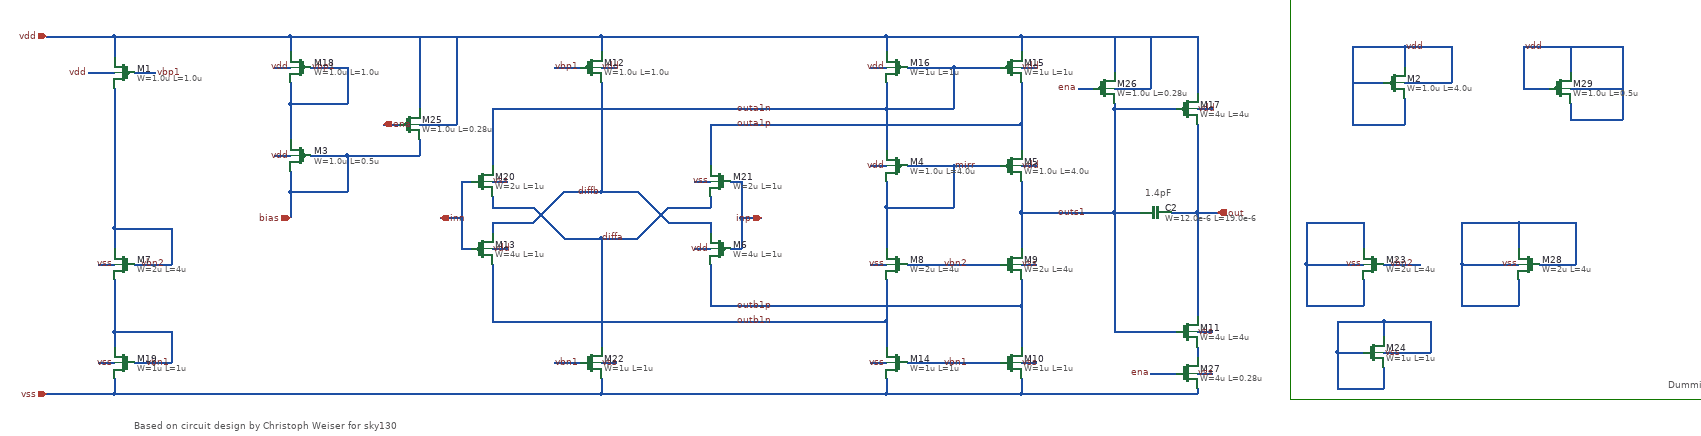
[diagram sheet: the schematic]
v {xschem version=3.4.6 file_version=1.2}
G {}
K {}
V {}
S {}
E {}
P 4 5 1810 -650 1810 140 2660 140 2660 -650 1810 -650 {}
T {Dummies} 2540 100 0 0 0.4 0.4 {}
T {Based on circuit design by Christoph Weiser for sky130} -420 180 0 0 0.4 0.4 {}
T {1.4pF} 1530 -270 0 0 0.3 0.3 {}
N 1000 -500 1030 -500 { lab=vdd}
N 1290 -500 1320 -500 { lab=vdd}
N 660 -280 690 -280 { lab=vss}
N 270 -280 300 -280 { lab=vss}
N 1030 -560 1030 -530 { lab=vdd}
N 270 -250 270 -230 { lab=diffa}
N 480 70 510 70 { lab=vss}
N -490 70 -460 70 { lab=vss}
N -420 -120 -350 -120 { lab=vbn2}
N -490 -120 -460 -120 { lab=vss}
N -420 70 -350 70 { lab=vbn1}
N -460 130 480 130 { lab=vss}
N -150 -500 -120 -500 { lab=vdd}
N 1290 -310 1320 -310 { lab=vdd}
N 1000 -310 1030 -310 { lab=vdd}
N 1160 -310 1250 -310 { lab=mirr}
N 1000 -120 1030 -120 { lab=vss}
N 1290 -120 1320 -120 { lab=vss}
N 1290 -220 1470 -220 { lab=outs1}
N 1000 70 1030 70 { lab=vss}
N 1290 70 1320 70 { lab=vss}
N -590 130 -460 130 { lab=vss}
N 1160 -500 1250 -500 { lab=outa1n}
N 1290 -560 1290 -530 { lab=vdd}
N 1030 -560 1290 -560 { lab=vdd}
N -80 -500 -10 -500 { lab=vbp1}
N 480 -560 1030 -560 { lab=vdd}
N -460 -190 -460 -150 { lab=vbn2}
N -460 10 -350 10 { lab=vbn1}
N -350 10 -350 70 { lab=vbn1}
N -350 -190 -350 -120 { lab=vbn2}
N -460 -190 -350 -190 { lab=vbn2}
N 390 70 450 70 { lab=vbn1}
N -150 -330 -120 -330 { lab=vdd}
N -80 -330 -10 -330 { lab=bias}
N 270 -420 270 -310 { lab=outa1n}
N 690 -390 690 -310 { lab=outa1p}
N -10 -330 -10 -260 { lab=bias}
N -460 10 -460 40 { lab=vbn1}
N -10 -500 -10 -430 { lab=vbp1}
N -120 -560 -120 -530 { lab=vdd}
N -120 -260 -10 -260 { lab=bias}
N -120 -430 -120 -360 { lab=vbp1}
N -120 -430 -10 -430 { lab=vbp1}
N 170 -210 210 -210 { lab=inn}
N 210 -150 230 -150 { lab=inn}
N -460 100 -460 130 { lab=vss}
N 270 -150 300 -150 { lab=vdd}
N 660 -150 690 -150 { lab=vdd}
N 270 -200 270 -180 { lab=diffb}
N 270 -200 350 -200 { lab=diffb}
N 350 -200 410 -260 { lab=diffb}
N 270 -230 350 -230 { lab=diffa}
N 350 -230 410 -170 { lab=diffa}
N 690 -250 690 -230 { lab=diffa}
N 690 -200 690 -180 { lab=diffb}
N 610 -200 690 -200 { lab=diffb}
N 550 -260 610 -200 { lab=diffb}
N 610 -230 690 -230 { lab=diffa}
N 550 -170 610 -230 { lab=diffa}
N 480 -260 550 -260 { lab=diffb}
N 480 -170 550 -170 { lab=diffa}
N 480 -560 480 -530 { lab=vdd}
N 210 -280 230 -280 { lab=inn}
N 210 -210 210 -150 { lab=inn}
N 750 -210 790 -210 { lab=inp}
N 730 -150 750 -150 { lab=inp}
N 730 -280 750 -280 { lab=inp}
N 750 -210 750 -150 { lab=inp}
N 270 -420 1030 -420 { lab=outa1n}
N 690 -390 1290 -390 { lab=outa1p}
N 1030 -420 1030 -340 { lab=outa1n}
N 1290 -390 1290 -340 { lab=outa1p}
N 480 -470 480 -260 { lab=diffb}
N 480 -170 480 40 { lab=diffa}
N 480 100 480 130 { lab=vss}
N 270 -120 270 -10 { lab=outb1n}
N 690 -120 690 -40 { lab=outb1p}
N 270 -10 1030 -10 { lab=outb1n}
N 690 -40 1290 -40 { lab=outb1p}
N 1030 100 1030 130 { lab=vss}
N 1070 70 1250 70 { lab=vbn1}
N 1070 -120 1250 -120 { lab=vbn2}
N 1290 100 1290 130 { lab=vss}
N 1030 -10 1030 40 { lab=outb1n}
N 1290 -40 1290 40 { lab=outb1p}
N 1030 -230 1030 -150 { lab=mirr}
N 1290 -220 1290 -150 { lab=outs1}
N 1030 130 1290 130 { lab=vss}
N 390 -500 440 -500 { lab=vbp1}
N 480 -500 510 -500 { lab=vdd}
N 1630 -420 1660 -420 { lab=vdd}
N 1630 10 1660 10 { lab=vss}
N 1470 10 1590 10 { lab=outs1}
N 1470 -220 1470 10 { lab=outs1}
N 1470 -420 1470 -220 { lab=outs1}
N 1470 -420 1590 -420 { lab=outs1}
N 1630 -220 1630 -20 { lab=out}
N 1630 -390 1630 -220 { lab=out}
N 1630 -220 1670 -220 { lab=out}
N 1470 -220 1520 -220 { lab=outs1}
N 1580 -220 1630 -220 { lab=out}
N 1290 -560 1630 -560 { lab=vdd}
N 1630 -560 1630 -450 { lab=vdd}
N 1290 130 1630 130 { lab=vss}
N 1030 -420 1160 -420 { lab=outa1n}
N 1160 -500 1160 -420 { lab=outa1n}
N 1030 -230 1160 -230 { lab=mirr}
N 1160 -310 1160 -230 { lab=mirr}
N 1290 -280 1290 -220 { lab=outs1}
N -460 -90 -460 10 { lab=vbn1}
N -120 -300 -120 -260 { lab=bias}
N -120 -470 -120 -430 { lab=vbp1}
N 210 -280 210 -210 { lab=inn}
N -120 -560 480 -560 { lab=vdd}
N 750 -280 750 -210 { lab=inp}
N 1030 -470 1030 -420 { lab=outa1n}
N 1290 -470 1290 -390 { lab=outa1p}
N 410 -260 480 -260 { lab=diffb}
N 410 -170 480 -170 { lab=diffa}
N 1030 -90 1030 -10 { lab=outb1n}
N 1290 -90 1290 -40 { lab=outb1p}
N 480 130 1030 130 { lab=vss}
N 1070 -500 1160 -500 { lab=outa1n}
N 1030 -280 1030 -230 { lab=mirr}
N 1070 -310 1160 -310 { lab=mirr}
N -460 -560 -120 -560 {lab=vdd}
N -460 -560 -460 -520 {lab=vdd}
N -510 -490 -460 -490 {lab=vdd}
N -420 -490 -380 -490 {lab=vbp1}
N -590 -560 -460 -560 {lab=vdd}
N -460 -460 -460 -190 {lab=vbn2}
N -120 -260 -120 -210 {lab=bias}
N 1990 50 2080 50 { lab=vss}
N 1900 50 1960 50 { lab=vss}
N 2080 -10 2080 50 {lab=vss}
N 1990 -10 2080 -10 {lab=vss}
N 1900 50 1900 120 {lab=vss}
N 1900 -10 1900 50 {lab=vss}
N 1900 120 1990 120 {lab=vss}
N 1990 80 1990 120 {lab=vss}
N 1990 -10 1990 20 {lab=vss}
N 1900 -10 1990 -10 {lab=vss}
N 1990 -120 2060 -120 { lab=vbn2}
N 1950 -200 1950 -150 {lab=vss}
N 1840 -200 1950 -200 {lab=vss}
N 1840 -120 1840 -40 {lab=vss}
N 1840 -40 1950 -40 {lab=vss}
N 1950 -90 1950 -40 {lab=vss}
N 1840 -120 1950 -120 {lab=vss}
N 1840 -200 1840 -120 {lab=vss}
N 130 -390 200 -390 {lab=vdd}
N 200 -560 200 -390 {lab=vdd}
N 130 -560 130 -420 {lab=vdd}
N 60 -390 90 -390 {lab=ena}
N -10 -330 130 -330 {lab=bias}
N 130 -360 130 -330 {lab=bias}
N 1470 -430 1470 -420 {lab=outs1}
N 1470 -560 1470 -490 {lab=vdd}
N 1470 -460 1540 -460 {lab=vdd}
N 1540 -560 1540 -460 {lab=vdd}
N 1400 -460 1430 -460 {lab=ena}
N 1630 120 1630 130 {lab=vss}
N 1630 40 1630 60 {lab=#net1}
N 1630 90 1660 90 { lab=vss}
N 1540 90 1590 90 {lab=ena}
N 2030 -540 2030 -500 {lab=vdd}
N 1930 -540 2030 -540 {lab=vdd}
N 1930 -540 1930 -390 {lab=vdd}
N 1930 -390 2030 -390 {lab=vdd}
N 2030 -440 2030 -390 {lab=vdd}
N 1930 -470 1990 -470 {lab=vdd}
N 2030 -540 2120 -540 {lab=vdd}
N 2120 -540 2120 -470 {lab=vdd}
N 2030 -470 2120 -470 {lab=vdd}
N 2290 -120 2360 -120 { lab=vss}
N 2250 -200 2250 -150 {lab=vss}
N 2140 -200 2250 -200 {lab=vss}
N 2140 -120 2140 -40 {lab=vss}
N 2140 -40 2250 -40 {lab=vss}
N 2250 -90 2250 -40 {lab=vss}
N 2140 -120 2250 -120 {lab=vss}
N 2140 -200 2140 -120 {lab=vss}
N 2360 -200 2360 -120 {lab=vss}
N 2250 -200 2360 -200 {lab=vss}
N 2260 -460 2310 -460 {lab=vdd}
N 2260 -540 2260 -460 {lab=vdd}
N 2260 -540 2450 -540 {lab=vdd}
N 2450 -540 2450 -400 {lab=vdd}
N 2350 -400 2450 -400 {lab=vdd}
N 2350 -430 2350 -400 {lab=vdd}
N 2350 -540 2350 -490 {lab=vdd}
N 2350 -460 2450 -460 {lab=vdd}
C {devices/iopin.sym} -590 -560 2 0 {name=p5 lab=vdd}
C {devices/iopin.sym} -120 -210 1 0 {name=p2 lab=bias}
C {devices/lab_wire.sym} 1030 -500 0 0 {name=l4 sig_type=std_logic lab=vdd}
C {devices/lab_wire.sym} 1290 -500 0 1 {name=l7 sig_type=std_logic lab=vdd}
C {devices/lab_wire.sym} 690 -280 0 0 {name=l8 sig_type=std_logic lab=vss}
C {devices/lab_wire.sym} 270 -280 0 1 {name=l9 sig_type=std_logic lab=vss}
C {devices/ipin.sym} 790 -210 2 0 {name=p7 lab=inp}
C {devices/ipin.sym} 170 -210 2 1 {name=p8 lab=inn}
C {devices/lab_wire.sym} 480 70 0 1 {name=l10 sig_type=std_logic lab=vss}
C {devices/lab_wire.sym} -460 70 0 0 {name=l13 sig_type=std_logic lab=vss}
C {devices/iopin.sym} -590 130 2 0 {name=p10 lab=vss}
C {devices/lab_wire.sym} 480 -170 0 1 {name=l1 sig_type=std_logic lab=diffa}
C {devices/lab_wire.sym} -400 70 0 1 {name=l14 sig_type=std_logic lab=vbn1}
C {devices/lab_wire.sym} -460 -120 0 0 {name=l15 sig_type=std_logic lab=vss}
C {devices/lab_wire.sym} -120 -500 0 0 {name=l21 sig_type=std_logic lab=vdd}
C {devices/lab_wire.sym} 1290 -310 0 1 {name=l20 sig_type=std_logic lab=vdd}
C {devices/lab_wire.sym} 1030 -310 0 0 {name=l24 sig_type=std_logic lab=vdd}
C {devices/lab_wire.sym} 1030 -120 0 0 {name=l26 sig_type=std_logic lab=vss}
C {devices/lab_wire.sym} 1290 -120 0 1 {name=l27 sig_type=std_logic lab=vss}
C {devices/lab_wire.sym} 1030 70 0 0 {name=l29 sig_type=std_logic lab=vss}
C {devices/lab_wire.sym} 1290 70 0 1 {name=l30 sig_type=std_logic lab=vss}
C {devices/lab_wire.sym} 1140 70 0 1 {name=l31 sig_type=std_logic lab=vbn1
}
C {devices/lab_wire.sym} 740 -390 0 1 {name=l33 sig_type=std_logic lab=outa1p
}
C {devices/lab_wire.sym} 740 -420 0 1 {name=l34 sig_type=std_logic lab=outa1n
}
C {devices/lab_wire.sym} -80 -500 0 1 {name=l17 sig_type=std_logic lab=vbp1}
C {devices/lab_wire.sym} 440 70 0 0 {name=l5 sig_type=std_logic lab=vbn1}
C {devices/lab_wire.sym} -120 -330 0 0 {name=l12 sig_type=std_logic lab=vdd}
C {devices/lab_wire.sym} 270 -150 0 1 {name=l6 sig_type=std_logic lab=vdd}
C {devices/lab_wire.sym} 690 -150 0 0 {name=l16 sig_type=std_logic lab=vdd}
C {devices/lab_wire.sym} 480 -260 0 0 {name=l23 sig_type=std_logic lab=diffb
}
C {devices/lab_wire.sym} 440 -500 0 0 {name=l11 sig_type=std_logic lab=vbp1}
C {devices/lab_wire.sym} 740 -40 0 1 {name=l19 sig_type=std_logic lab=outb1p
}
C {devices/lab_wire.sym} 740 -10 0 1 {name=l25 sig_type=std_logic lab=outb1n
}
C {devices/lab_wire.sym} 480 -500 0 1 {name=l28 sig_type=std_logic lab=vdd}
C {devices/lab_wire.sym} 1160 -310 0 1 {name=l32 sig_type=std_logic lab=mirr
}
C {devices/opin.sym} 1670 -220 0 0 {name=p1 lab=out}
C {devices/lab_wire.sym} 1630 -420 0 1 {name=l35 sig_type=std_logic lab=vdd}
C {devices/lab_wire.sym} 1630 10 0 1 {name=l36 sig_type=std_logic lab=vss}
C {devices/lab_wire.sym} 1360 -220 0 1 {name=l37 sig_type=std_logic lab=outs1
}
C {devices/lab_wire.sym} 1140 -120 0 1 {name=l3 sig_type=std_logic lab=vbn2
}
C {devices/lab_wire.sym} -410 -120 0 1 {name=l56 sig_type=std_logic lab=vbn2}
C {lab_pin.sym} -380 -490 0 1 {name=p3 sig_type=std_logic lab=vbp1}
C {lab_wire.sym} -510 -490 0 0 {name=p6 sig_type=std_logic lab=vdd}
C {devices/lab_wire.sym} 1990 50 0 1 {name=l18 sig_type=std_logic lab=vss}
C {devices/lab_wire.sym} 1950 -120 0 0 {name=l22 sig_type=std_logic lab=vss}
C {devices/lab_wire.sym} 2000 -120 0 1 {name=l38 sig_type=std_logic lab=vbn2}
C {gf180mcu_fd_pr/cap_mim_2f0fF.sym} 1550 -220 1 0 {name=C2
W=12.0e-6
L=19.0e-6
model=cap_mim_2f0_m4m5_noshield
spiceprefix=X
m=3}
C {gf180mcu_fd_pr/pfet_03v3.sym} -440 -490 0 1 {name=M1
L=1.0u
W=1.0u
nf=1
m=4
ad="'int((nf+1)/2) * W/nf * 0.18u'"
pd="'2*int((nf+1)/2) * (W/nf + 0.18u)'"
as="'int((nf+2)/2) * W/nf * 0.18u'"
ps="'2*int((nf+2)/2) * (W/nf + 0.18u)'"
nrd="'0.18u / W'" nrs="'0.18u / W'"
sa=0 sb=0 sd=0
model=pfet_03v3
spiceprefix=X
}
C {gf180mcu_fd_pr/pfet_03v3.sym} -100 -330 0 1 {name=M3
L=0.5u
W=1.0u
nf=1
m=12
ad="'int((nf+1)/2) * W/nf * 0.18u'"
pd="'2*int((nf+1)/2) * (W/nf + 0.18u)'"
as="'int((nf+2)/2) * W/nf * 0.18u'"
ps="'2*int((nf+2)/2) * (W/nf + 0.18u)'"
nrd="'0.18u / W'" nrs="'0.18u / W'"
sa=0 sb=0 sd=0
model=pfet_03v3
spiceprefix=X
}
C {gf180mcu_fd_pr/pfet_03v3.sym} 460 -500 0 0 {name=M12
L=1.0u
W=1.0u
nf=1
m=16
ad="'int((nf+1)/2) * W/nf * 0.18u'"
pd="'2*int((nf+1)/2) * (W/nf + 0.18u)'"
as="'int((nf+2)/2) * W/nf * 0.18u'"
ps="'2*int((nf+2)/2) * (W/nf + 0.18u)'"
nrd="'0.18u / W'" nrs="'0.18u / W'"
sa=0 sb=0 sd=0
model=pfet_03v3
spiceprefix=X
}
C {gf180mcu_fd_pr/pfet_03v3.sym} 250 -150 0 0 {name=M13
L=1u
W=4u
nf=1
m=8
ad="'int((nf+1)/2) * W/nf * 0.18u'"
pd="'2*int((nf+1)/2) * (W/nf + 0.18u)'"
as="'int((nf+2)/2) * W/nf * 0.18u'"
ps="'2*int((nf+2)/2) * (W/nf + 0.18u)'"
nrd="'0.18u / W'" nrs="'0.18u / W'"
sa=0 sb=0 sd=0
model=pfet_03v3
spiceprefix=X
}
C {gf180mcu_fd_pr/pfet_03v3.sym} 1050 -500 0 1 {name=M16
L=1u
W=1u
nf=1
m=12
ad="'int((nf+1)/2) * W/nf * 0.18u'"
pd="'2*int((nf+1)/2) * (W/nf + 0.18u)'"
as="'int((nf+2)/2) * W/nf * 0.18u'"
ps="'2*int((nf+2)/2) * (W/nf + 0.18u)'"
nrd="'0.18u / W'" nrs="'0.18u / W'"
sa=0 sb=0 sd=0
model=pfet_03v3
spiceprefix=X
}
C {gf180mcu_fd_pr/pfet_03v3.sym} 1610 -420 0 0 {name=M17
L=4u
W=4u
nf=1
m=4
ad="'int((nf+1)/2) * W/nf * 0.18u'"
pd="'2*int((nf+1)/2) * (W/nf + 0.18u)'"
as="'int((nf+2)/2) * W/nf * 0.18u'"
ps="'2*int((nf+2)/2) * (W/nf + 0.18u)'"
nrd="'0.18u / W'" nrs="'0.18u / W'"
sa=0 sb=0 sd=0
model=pfet_03v3
spiceprefix=X
}
C {gf180mcu_fd_pr/pfet_03v3.sym} -100 -500 0 1 {name=M18
L=1.0u
W=1.0u
nf=1
m=4
ad="'int((nf+1)/2) * W/nf * 0.18u'"
pd="'2*int((nf+1)/2) * (W/nf + 0.18u)'"
as="'int((nf+2)/2) * W/nf * 0.18u'"
ps="'2*int((nf+2)/2) * (W/nf + 0.18u)'"
nrd="'0.18u / W'" nrs="'0.18u / W'"
sa=0 sb=0 sd=0
model=pfet_03v3
spiceprefix=X
}
C {gf180mcu_fd_pr/pfet_03v3.sym} 1270 -500 0 0 {name=M15
L=1u
W=1u
nf=1
m=12
ad="'int((nf+1)/2) * W/nf * 0.18u'"
pd="'2*int((nf+1)/2) * (W/nf + 0.18u)'"
as="'int((nf+2)/2) * W/nf * 0.18u'"
ps="'2*int((nf+2)/2) * (W/nf + 0.18u)'"
nrd="'0.18u / W'" nrs="'0.18u / W'"
sa=0 sb=0 sd=0
model=pfet_03v3
spiceprefix=X
}
C {gf180mcu_fd_pr/pfet_03v3.sym} 1050 -310 0 1 {name=M4
L=4.0u
W=1.0u
nf=1
m=16
ad="'int((nf+1)/2) * W/nf * 0.18u'"
pd="'2*int((nf+1)/2) * (W/nf + 0.18u)'"
as="'int((nf+2)/2) * W/nf * 0.18u'"
ps="'2*int((nf+2)/2) * (W/nf + 0.18u)'"
nrd="'0.18u / W'" nrs="'0.18u / W'"
sa=0 sb=0 sd=0
model=pfet_03v3
spiceprefix=X
}
C {gf180mcu_fd_pr/pfet_03v3.sym} 1270 -310 0 0 {name=M5
L=4.0u
W=1.0u
nf=1
m=16
ad="'int((nf+1)/2) * W/nf * 0.18u'"
pd="'2*int((nf+1)/2) * (W/nf + 0.18u)'"
as="'int((nf+2)/2) * W/nf * 0.18u'"
ps="'2*int((nf+2)/2) * (W/nf + 0.18u)'"
nrd="'0.18u / W'" nrs="'0.18u / W'"
sa=0 sb=0 sd=0
model=pfet_03v3
spiceprefix=X
}
C {gf180mcu_fd_pr/pfet_03v3.sym} 710 -150 0 1 {name=M6
L=1u
W=4u
nf=1
m=8
ad="'int((nf+1)/2) * W/nf * 0.18u'"
pd="'2*int((nf+1)/2) * (W/nf + 0.18u)'"
as="'int((nf+2)/2) * W/nf * 0.18u'"
ps="'2*int((nf+2)/2) * (W/nf + 0.18u)'"
nrd="'0.18u / W'" nrs="'0.18u / W'"
sa=0 sb=0 sd=0
model=pfet_03v3
spiceprefix=X
}
C {gf180mcu_fd_pr/nfet_03v3.sym} -440 -120 0 1 {name=M7
L=4u
W=2u
nf=1
m=4
ad="'int((nf+1)/2) * W/nf * 0.18u'"
pd="'2*int((nf+1)/2) * (W/nf + 0.18u)'"
as="'int((nf+2)/2) * W/nf * 0.18u'"
ps="'2*int((nf+2)/2) * (W/nf + 0.18u)'"
nrd="'0.18u / W'" nrs="'0.18u / W'"
sa=0 sb=0 sd=0
model=nfet_03v3
spiceprefix=X
}
C {gf180mcu_fd_pr/nfet_03v3.sym} -440 70 0 1 {name=M19
L=1u
W=1u
nf=1
m=4
ad="'int((nf+1)/2) * W/nf * 0.18u'"
pd="'2*int((nf+1)/2) * (W/nf + 0.18u)'"
as="'int((nf+2)/2) * W/nf * 0.18u'"
ps="'2*int((nf+2)/2) * (W/nf + 0.18u)'"
nrd="'0.18u / W'" nrs="'0.18u / W'"
sa=0 sb=0 sd=0
model=nfet_03v3
spiceprefix=X
}
C {gf180mcu_fd_pr/nfet_03v3.sym} 250 -280 0 0 {name=M20
L=1u
W=2u
nf=1
m=8
ad="'int((nf+1)/2) * W/nf * 0.18u'"
pd="'2*int((nf+1)/2) * (W/nf + 0.18u)'"
as="'int((nf+2)/2) * W/nf * 0.18u'"
ps="'2*int((nf+2)/2) * (W/nf + 0.18u)'"
nrd="'0.18u / W'" nrs="'0.18u / W'"
sa=0 sb=0 sd=0
model=nfet_03v3
spiceprefix=X
}
C {gf180mcu_fd_pr/nfet_03v3.sym} 710 -280 0 1 {name=M21
L=1u
W=2u
nf=1
m=8
ad="'int((nf+1)/2) * W/nf * 0.18u'"
pd="'2*int((nf+1)/2) * (W/nf + 0.18u)'"
as="'int((nf+2)/2) * W/nf * 0.18u'"
ps="'2*int((nf+2)/2) * (W/nf + 0.18u)'"
nrd="'0.18u / W'" nrs="'0.18u / W'"
sa=0 sb=0 sd=0
model=nfet_03v3
spiceprefix=X
}
C {gf180mcu_fd_pr/nfet_03v3.sym} 460 70 0 0 {name=M22
L=1u
W=1u
nf=1
m=8
ad="'int((nf+1)/2) * W/nf * 0.18u'"
pd="'2*int((nf+1)/2) * (W/nf + 0.18u)'"
as="'int((nf+2)/2) * W/nf * 0.18u'"
ps="'2*int((nf+2)/2) * (W/nf + 0.18u)'"
nrd="'0.18u / W'" nrs="'0.18u / W'"
sa=0 sb=0 sd=0
model=nfet_03v3
spiceprefix=X
}
C {gf180mcu_fd_pr/nfet_03v3.sym} 1050 70 0 1 {name=M14
L=1u
W=1u
nf=1
m=24
ad="'int((nf+1)/2) * W/nf * 0.18u'"
pd="'2*int((nf+1)/2) * (W/nf + 0.18u)'"
as="'int((nf+2)/2) * W/nf * 0.18u'"
ps="'2*int((nf+2)/2) * (W/nf + 0.18u)'"
nrd="'0.18u / W'" nrs="'0.18u / W'"
sa=0 sb=0 sd=0
model=nfet_03v3
spiceprefix=X
}
C {gf180mcu_fd_pr/nfet_03v3.sym} 1270 70 0 0 {name=M10
L=1u
W=1u
nf=1
m=24
ad="'int((nf+1)/2) * W/nf * 0.18u'"
pd="'2*int((nf+1)/2) * (W/nf + 0.18u)'"
as="'int((nf+2)/2) * W/nf * 0.18u'"
ps="'2*int((nf+2)/2) * (W/nf + 0.18u)'"
nrd="'0.18u / W'" nrs="'0.18u / W'"
sa=0 sb=0 sd=0
model=nfet_03v3
spiceprefix=X
}
C {gf180mcu_fd_pr/nfet_03v3.sym} 1050 -120 0 1 {name=M8
L=4u
W=2u
nf=1
m=16
ad="'int((nf+1)/2) * W/nf * 0.18u'"
pd="'2*int((nf+1)/2) * (W/nf + 0.18u)'"
as="'int((nf+2)/2) * W/nf * 0.18u'"
ps="'2*int((nf+2)/2) * (W/nf + 0.18u)'"
nrd="'0.18u / W'" nrs="'0.18u / W'"
sa=0 sb=0 sd=0
model=nfet_03v3
spiceprefix=X
}
C {gf180mcu_fd_pr/nfet_03v3.sym} 1270 -120 0 0 {name=M9
L=4u
W=2u
nf=1
m=16
ad="'int((nf+1)/2) * W/nf * 0.18u'"
pd="'2*int((nf+1)/2) * (W/nf + 0.18u)'"
as="'int((nf+2)/2) * W/nf * 0.18u'"
ps="'2*int((nf+2)/2) * (W/nf + 0.18u)'"
nrd="'0.18u / W'" nrs="'0.18u / W'"
sa=0 sb=0 sd=0
model=nfet_03v3
spiceprefix=X
}
C {gf180mcu_fd_pr/nfet_03v3.sym} 1610 10 0 0 {name=M11
L=4u
W=4u
nf=1
m=4
ad="'int((nf+1)/2) * W/nf * 0.18u'"
pd="'2*int((nf+1)/2) * (W/nf + 0.18u)'"
as="'int((nf+2)/2) * W/nf * 0.18u'"
ps="'2*int((nf+2)/2) * (W/nf + 0.18u)'"
nrd="'0.18u / W'" nrs="'0.18u / W'"
sa=0 sb=0 sd=0
model=nfet_03v3
spiceprefix=X
}
C {gf180mcu_fd_pr/nfet_03v3.sym} 1970 -120 0 1 {name=M23
L=4u
W=2u
nf=1
m=4
ad="'int((nf+1)/2) * W/nf * 0.18u'"
pd="'2*int((nf+1)/2) * (W/nf + 0.18u)'"
as="'int((nf+2)/2) * W/nf * 0.18u'"
ps="'2*int((nf+2)/2) * (W/nf + 0.18u)'"
nrd="'0.18u / W'" nrs="'0.18u / W'"
sa=0 sb=0 sd=0
model=nfet_03v3
spiceprefix=X
}
C {gf180mcu_fd_pr/nfet_03v3.sym} 1970 50 0 0 {name=M24
L=1u
W=1u
nf=1
m=12
ad="'int((nf+1)/2) * W/nf * 0.18u'"
pd="'2*int((nf+1)/2) * (W/nf + 0.18u)'"
as="'int((nf+2)/2) * W/nf * 0.18u'"
ps="'2*int((nf+2)/2) * (W/nf + 0.18u)'"
nrd="'0.18u / W'" nrs="'0.18u / W'"
sa=0 sb=0 sd=0
model=nfet_03v3
spiceprefix=X
}
C {gf180mcu_fd_pr/pfet_03v3.sym} 110 -390 0 0 {name=M25
L=0.28u
W=1.0u
nf=1
m=1
ad="'int((nf+1)/2) * W/nf * 0.18u'"
pd="'2*int((nf+1)/2) * (W/nf + 0.18u)'"
as="'int((nf+2)/2) * W/nf * 0.18u'"
ps="'2*int((nf+2)/2) * (W/nf + 0.18u)'"
nrd="'0.18u / W'" nrs="'0.18u / W'"
sa=0 sb=0 sd=0
model=pfet_03v3
spiceprefix=X
}
C {devices/ipin.sym} 60 -390 2 1 {name=p9 lab=ena}
C {gf180mcu_fd_pr/pfet_03v3.sym} 1450 -460 0 0 {name=M26
L=0.28u
W=1.0u
nf=1
m=1
ad="'int((nf+1)/2) * W/nf * 0.18u'"
pd="'2*int((nf+1)/2) * (W/nf + 0.18u)'"
as="'int((nf+2)/2) * W/nf * 0.18u'"
ps="'2*int((nf+2)/2) * (W/nf + 0.18u)'"
nrd="'0.18u / W'" nrs="'0.18u / W'"
sa=0 sb=0 sd=0
model=pfet_03v3
spiceprefix=X
}
C {lab_pin.sym} 1400 -460 0 0 {name=p11 sig_type=std_logic lab=ena}
C {gf180mcu_fd_pr/nfet_03v3.sym} 1610 90 0 0 {name=M27
L=0.28u
W=4u
nf=1
m=8
ad="'int((nf+1)/2) * W/nf * 0.18u'"
pd="'2*int((nf+1)/2) * (W/nf + 0.18u)'"
as="'int((nf+2)/2) * W/nf * 0.18u'"
ps="'2*int((nf+2)/2) * (W/nf + 0.18u)'"
nrd="'0.18u / W'" nrs="'0.18u / W'"
sa=0 sb=0 sd=0
model=nfet_03v3
spiceprefix=X
}
C {devices/lab_wire.sym} 1630 90 0 1 {name=l39 sig_type=std_logic lab=vss}
C {lab_pin.sym} 1540 90 0 0 {name=p12 sig_type=std_logic lab=ena}
C {gf180mcu_fd_pr/pfet_03v3.sym} 2010 -470 0 0 {name=M2
L=4.0u
W=1.0u
nf=1
m=4
ad="'int((nf+1)/2) * W/nf * 0.18u'"
pd="'2*int((nf+1)/2) * (W/nf + 0.18u)'"
as="'int((nf+2)/2) * W/nf * 0.18u'"
ps="'2*int((nf+2)/2) * (W/nf + 0.18u)'"
nrd="'0.18u / W'" nrs="'0.18u / W'"
sa=0 sb=0 sd=0
model=pfet_03v3
spiceprefix=X
}
C {devices/lab_wire.sym} 2030 -540 0 1 {name=l2 sig_type=std_logic lab=vdd}
C {devices/lab_wire.sym} 2250 -120 0 0 {name=l40 sig_type=std_logic lab=vss}
C {gf180mcu_fd_pr/nfet_03v3.sym} 2270 -120 0 1 {name=M28
L=4u
W=2u
nf=1
m=4
ad="'int((nf+1)/2) * W/nf * 0.18u'"
pd="'2*int((nf+1)/2) * (W/nf + 0.18u)'"
as="'int((nf+2)/2) * W/nf * 0.18u'"
ps="'2*int((nf+2)/2) * (W/nf + 0.18u)'"
nrd="'0.18u / W'" nrs="'0.18u / W'"
sa=0 sb=0 sd=0
model=nfet_03v3
spiceprefix=X
}
C {gf180mcu_fd_pr/pfet_03v3.sym} 2330 -460 0 0 {name=M29
L=0.5u
W=1.0u
nf=1
m=12
ad="'int((nf+1)/2) * W/nf * 0.18u'"
pd="'2*int((nf+1)/2) * (W/nf + 0.18u)'"
as="'int((nf+2)/2) * W/nf * 0.18u'"
ps="'2*int((nf+2)/2) * (W/nf + 0.18u)'"
nrd="'0.18u / W'" nrs="'0.18u / W'"
sa=0 sb=0 sd=0
model=pfet_03v3
spiceprefix=X
}
C {devices/lab_wire.sym} 2260 -540 0 1 {name=l41 sig_type=std_logic lab=vdd}
